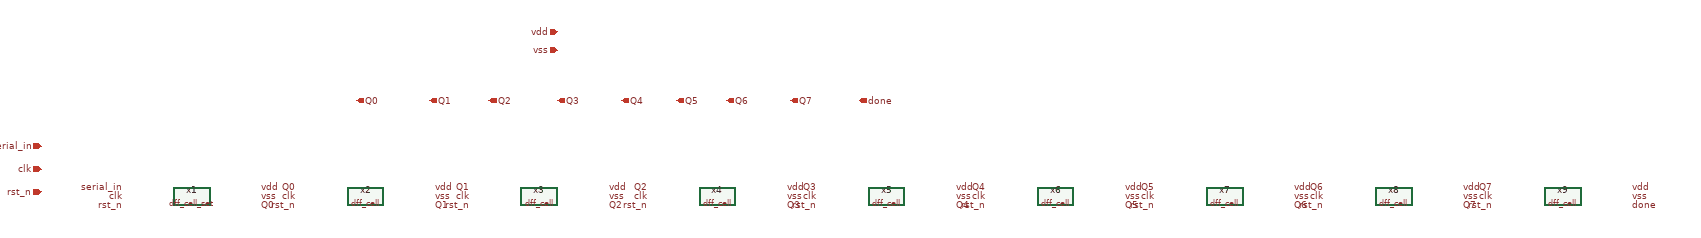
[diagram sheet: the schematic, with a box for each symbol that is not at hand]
v {xschem version=3.4.8RC file_version=1.3}
G {}
K {}
V {}
S {}
F {}
E {}
C {ipin.sym} -1720 -110 0 0 {name=p_sin lab=serial_in}
C {ipin.sym} -1720 -60 0 0 {name=p_clk lab=clk}
C {ipin.sym} -1720 -10 0 0 {name=p_rst lab=rst_n}
C {opin.sym} -1030 -210 0 0 {name=p_q0 lab=Q0}
C {lab_wire.sym} -1240 20 2 0 {name=l_q0 lab=Q0}
C {opin.sym} -870 -210 0 0 {name=p_q1 lab=Q1}
C {lab_wire.sym} -780 -20 0 0 {name=l_q1 lab=Q1}
C {opin.sym} -740 -210 0 0 {name=p_q2 lab=Q2}
C {lab_wire.sym} -390 -20 0 0 {name=l_q2 lab=Q2}
C {opin.sym} -590 -210 0 0 {name=p_q3 lab=Q3}
C {lab_wire.sym} -20 -20 0 0 {name=l_q3 lab=Q3}
C {opin.sym} -450 -210 0 0 {name=p_q4 lab=Q4}
C {lab_wire.sym} 350 -20 0 0 {name=l_q4 lab=Q4}
C {opin.sym} -330 -210 0 0 {name=p_q5 lab=Q5}
C {lab_wire.sym} 720 -20 0 0 {name=l_q5 lab=Q5}
C {opin.sym} -220 -210 0 0 {name=p_q6 lab=Q6}
C {lab_wire.sym} 1090 -20 0 0 {name=l_q6 lab=Q6}
C {opin.sym} -80 -210 0 0 {name=p_q7 lab=Q7}
C {lab_wire.sym} 1460 -20 0 0 {name=l_q7 lab=Q7}
C {opin.sym} 70 -210 0 0 {name=p_done lab=done}
C {lab_wire.sym} 1760 20 2 0 {name=l_done lab=done}
C {sar_adc/blocks/async_sar/dff_cell_set.sym} -1390 0 0 0 {name=x1}
C {lab_wire.sym} -1540 -20 0 0 {name=l_w_sin lab=serial_in}
C {lab_wire.sym} -1540 0 0 0 {name=l_w_clk0 lab=clk}
C {lab_wire.sym} -1540 20 0 0 {name=l_w_rst0 lab=rst_n}
C {sar_adc/blocks/async_sar/dff_cell.sym} -1010 0 0 0 {name=x2}
C {lab_wire.sym} -1160 0 0 0 {name=l_w_clk1 lab=clk}
C {lab_wire.sym} -1160 20 0 0 {name=l_w_rst1 lab=rst_n}
C {sar_adc/blocks/async_sar/dff_cell.sym} -630 0 0 0 {name=x3}
C {lab_wire.sym} -780 0 0 0 {name=l_w_clk2 lab=clk}
C {lab_wire.sym} -780 20 0 0 {name=l_w_rst2 lab=rst_n}
C {sar_adc/blocks/async_sar/dff_cell.sym} -240 0 0 0 {name=x4}
C {lab_wire.sym} -390 0 0 0 {name=l_w_clk3 lab=clk}
C {lab_wire.sym} -390 20 0 0 {name=l_w_rst3 lab=rst_n}
C {sar_adc/blocks/async_sar/dff_cell.sym} 130 0 0 0 {name=x5}
C {lab_wire.sym} -20 0 0 0 {name=l_w_clk4 lab=clk}
C {lab_wire.sym} -20 20 0 0 {name=l_w_rst4 lab=rst_n}
C {sar_adc/blocks/async_sar/dff_cell.sym} 500 0 0 0 {name=x6}
C {lab_wire.sym} 350 0 0 0 {name=l_w_clk5 lab=clk}
C {lab_wire.sym} 350 20 0 0 {name=l_w_rst5 lab=rst_n}
C {sar_adc/blocks/async_sar/dff_cell.sym} 870 0 0 0 {name=x7}
C {lab_wire.sym} 720 0 0 0 {name=l_w_clk6 lab=clk}
C {lab_wire.sym} 720 20 0 0 {name=l_w_rst6 lab=rst_n}
C {sar_adc/blocks/async_sar/dff_cell.sym} 1240 0 0 0 {name=x8}
C {lab_wire.sym} 1090 0 0 0 {name=l_w_clk7 lab=clk}
C {lab_wire.sym} 1090 20 0 0 {name=l_w_rst7 lab=rst_n}
C {sar_adc/blocks/async_sar/dff_cell.sym} 1610 0 0 0 {name=x9}
C {lab_wire.sym} 1460 0 0 0 {name=l_w_clk8 lab=clk}
C {lab_wire.sym} 1460 20 0 0 {name=l_w_rst8 lab=rst_n}
C {title.sym} -1350 270 0 0 {name=l_title author="Berkah Saluyu"}
C {lab_wire.sym} -1240 -20 2 0 {name=l_w_clk9 lab=vdd}
C {lab_wire.sym} -1160 -20 0 0 {name=l_q8 lab=Q0}
C {lab_wire.sym} -860 20 2 0 {name=l_q9 lab=Q1}
C {lab_wire.sym} -1240 0 2 0 {name=l_w_clk10 lab=vss}
C {lab_wire.sym} 1390 -20 2 0 {name=l_w_clk11 lab=vdd}
C {lab_wire.sym} 1390 20 2 0 {name=l_q10 lab=Q7}
C {lab_wire.sym} 1390 0 2 0 {name=l_w_clk12 lab=vss}
C {lab_wire.sym} 1760 -20 2 0 {name=l_w_clk13 lab=vdd}
C {lab_wire.sym} 1760 0 2 0 {name=l_w_clk14 lab=vss}
C {lab_wire.sym} 1020 20 2 0 {name=l_q11 lab=Q6}
C {lab_wire.sym} 1020 0 2 0 {name=l_w_clk15 lab=vss}
C {lab_wire.sym} 1020 -20 2 0 {name=l_w_clk16 lab=vdd}
C {lab_wire.sym} 650 20 2 0 {name=l_q12 lab=Q5}
C {lab_wire.sym} 650 -20 2 0 {name=l_w_clk17 lab=vdd}
C {lab_wire.sym} 650 0 2 0 {name=l_w_clk18 lab=vss}
C {lab_wire.sym} 280 20 2 0 {name=l_q13 lab=Q4}
C {lab_wire.sym} 280 0 2 0 {name=l_w_clk19 lab=vss}
C {lab_wire.sym} 280 -20 2 0 {name=l_w_clk20 lab=vdd}
C {lab_wire.sym} -90 20 2 0 {name=l_q14 lab=Q3}
C {lab_wire.sym} -90 0 2 0 {name=l_w_clk21 lab=vss}
C {lab_wire.sym} -90 -20 2 0 {name=l_w_clk22 lab=vdd}
C {lab_wire.sym} -480 20 2 0 {name=l_q15 lab=Q2}
C {lab_wire.sym} -480 -20 2 0 {name=l_w_clk23 lab=vdd}
C {lab_wire.sym} -480 0 2 0 {name=l_w_clk24 lab=vss}
C {lab_wire.sym} -860 -20 2 0 {name=l_w_clk25 lab=vdd}
C {lab_wire.sym} -860 0 2 0 {name=l_w_clk26 lab=vss}
C {iopin.sym} -590 -360 0 0 {name=p1 lab=vdd}
C {iopin.sym} -590 -320 0 0 {name=p2 lab=vss}
